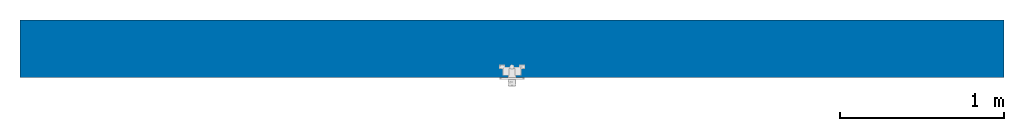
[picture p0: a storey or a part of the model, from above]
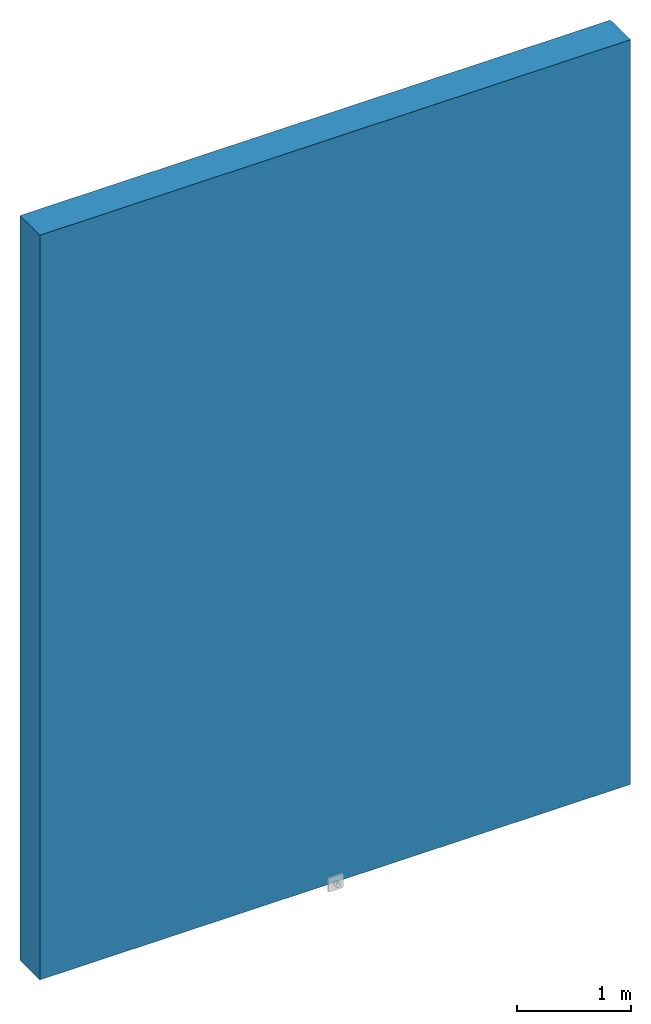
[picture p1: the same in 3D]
Properties of the parts of a building model (IFC2X3)

# File
Description: ViewDefinition [CoordinationView_V2.0]
File name: 0001
Time: 2024-08-26T16:25:12
Written by: The EXPRESS Data Manager Version 5.02.0100.07 : 28 Aug 2013
Made in: 21.1.90.15 - Exporter 21.1.90.15 - Alternate UI 21.1.90.15
Comment: STEP Physical File produced by: The EXPRESS Data Manager Version 5.02.0100.07 : 28 Aug 2013 * Module: EDMstepFileFactory/EDMstandAlone * Creation date: Mon Aug 26 16:25:12 2024 * Host: DCreative * Database: C:\Users\chatp\AppData\Local\Temp\0c0689ac-960f-49f8-8ed9-54e050225518\a585fe9f-b19c-4a9f-abce-4a98cb050a7e\ifc * Database version: 5507 * Database creation date: Mon Aug 26 16:25:09 2024 * Schema: IFC2X3 * Model: DataRepository.ifc * Model creation date: Mon Aug 26 16:25:09 2024 * Header model: DataRepository.ifc_HeaderModel * Header model creation date: Mon Aug 26 16:25:09 2024 * EDMuser: sdai-user * EDMgroup: sdai-group * License ID and type: 5605 : Permanent license. Expiry date: * EDMstepFileFactory options: 020000

# IfcProject, 0001
LongName: Project Name; Phase: Project Status

# IfcSite, Default
RefLatitude: 42, 21, 31, 181945; RefLongitude: -71, -3, -24, -263305; RefElevation: 0 mm
Pset_ProductRequirements - Category: Project Information

# IfcBuilding
Pset_BuildingCommon - NumberOfStoreys: 1
Pset_ProductRequirements - Category: Project Information

# IfcBuildingStorey: Level:8mm Head, Level 1
LongName: Level 1; Elevation: 0 mm
Pset_AirSideSystemInformation - Name: Level 1
Pset_ProductRequirements - Name: Level 1; Category: Levels

# IfcBuildingElementProxy: FFASS506-000600BV0_REVIT:ConcealThermostatic Mixer with Trim_HG, FFASS506-000600BV0_REVIT:ConcealThermostatic Mixer with Trim_HG:348440
In: Level 1
Type - Material: American Standard - Zinc Die Cast-Plastic, American Standard - Chrome
Type - Pset_BuildingElementProxyCommon - Reference: ConcealThermostatic Mixer with Trim_HG
Type - Pset_ManufacturerTypeInformation - Manufacturer: American Standard
Type - Pset_ProductRequirements - Category: Specialty Equipment
Type - Pset_QuantityTakeOff - Reference: ConcealThermostatic Mixer with Trim_HG
Type - Pset_ProvisionForVoid - Width: 151 mm; Height: 119 mm
Material: American Standard - Chrome
Pset_BuildingElementProxyCommon - sets with these values: 2

# IfcDistributionPort (3)
Description: Flow
Name | FlowDirection
2 x Port_348440 | SOURCE
Port_348440 | SINK

# IfcWallStandardCase: Basic Wall:Exterior - Brick on Mtl. Stud, Basic Wall:Exterior - Brick on Mtl. Stud:347042
In: Level 1
Type - PredefinedType: STANDARD
Type - Pset_ElementShading - Roughness: 914.4 mm
Type - Pset_ProductRequirements - Category: Walls
Type - Pset_QuantityTakeOff - Reference: Exterior - Brick on Mtl. Stud
Type - Pset_ReinforcementBarPitchOfWall - Reference: Exterior - Brick on Mtl. Stud
Type - Pset_WallCommon - Reference: Exterior - Brick on Mtl. Stud; IsExternal: no
Pset_QuantityTakeOff - sets with these values: 2
Pset_WallCommon - IsExternal: yes; ExtendToStructure: no; LoadBearing: no
